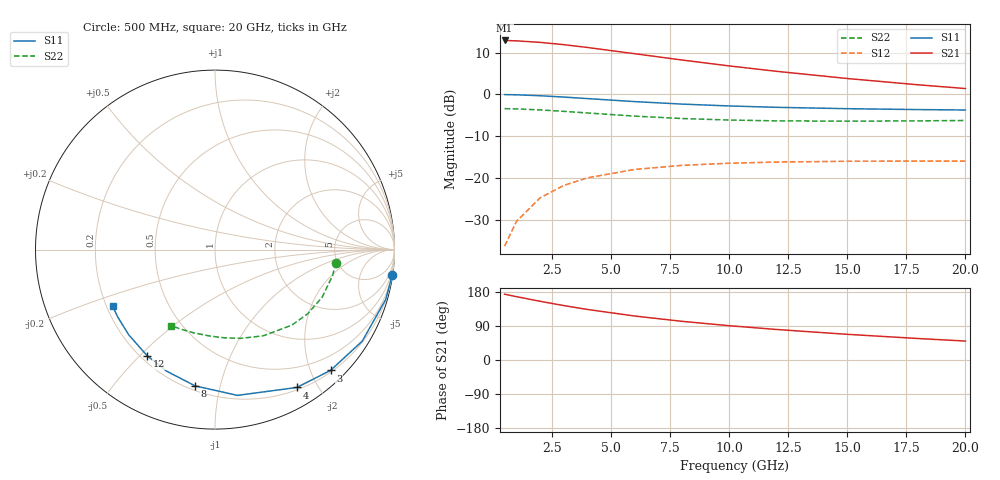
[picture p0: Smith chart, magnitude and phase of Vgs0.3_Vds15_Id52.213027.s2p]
# Hz S RI R 50
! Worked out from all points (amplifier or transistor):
!   12 points, 500 MHz to 20 GHz, reference 50 ohm
!   highest |S21| = 13.0 dB at 500 MHz (marker M1)
!   |S21| within 3 dB of that: start of sweep to 5.764 GHz
!   unconditionally stable (mu >= 1): 19.36 GHz to end of sweep
!   at 2 GHz: K = 0.10, MSG = 18.6 dB, |S12| = -24.8 dB
!   at 8 GHz: K = 0.40, MSG = 12.6 dB, |S12| = -17.0 dB
!   at 20 GHz: K = 1.04, MAG = 7.5 dB, |S12| = -16.0 dB
!   S11 on the Smith chart (normalised r, x): 500 MHz: 0, -14; 3 GHz: 0.23, -2.32; 4 GHz: 0.23, -1.73; 8 GHz: 0.23, -0.84; 12 GHz: 0.23, -0.53; 20 GHz: 0.22, -0.25
5e8  0.9876 -0.1418  -4.416 0.4976  0.00146 0.0151  0.6725 -0.0726
1e9  0.9513 -0.2773  -4.286 0.9728  0.00573 0.0295  0.6561 -0.1425
2e9  0.8207 -0.5097  -3.819 1.784  0.0211 0.0536  0.5969 -0.2655
3e9  0.6437 -0.6731  -3.187 2.346  0.0417 0.0696  0.516 -0.3581
4e9  0.4553 -0.7683  -2.517 2.662  0.0636 0.0773  0.4285 -0.4207
6e9  0.1251 -0.8122  -1.355 2.769  0.1011 0.0757  0.2692 -0.4802
8e9  -0.1112 -0.7592  -0.5433 2.533  0.1266 0.0628  0.1452 -0.4944
1e10  -0.2702 -0.6768  -0.0201 2.202  0.1424 0.0471  0.0503 -0.4913
1.2e10  -0.3777 -0.5916  0.3104 1.871  0.1516 0.0316  -0.0257 -0.4821
1.5e10  -0.4803 -0.4752  0.5884 1.439  0.1578 0.0111  -0.1187 -0.4638
1.8e10  -0.5422 -0.3752  0.7179 1.092  0.159 -0.00595  -0.1965 -0.4412
2e10  -0.5697 -0.3163  0.7573 0.9024  0.1583 -0.0157  -0.2424 -0.4235
